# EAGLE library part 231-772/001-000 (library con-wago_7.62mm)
Serie 231, Stiftleiste mit geraden Einlötstiften / Series 231, Male connector with straight solder pins Polzahl / Pole No.: 12 Rastermaß / Pitch: 7.62 mm Bemessungsspannung / Rated Voltage: 630 V Nennstrom / Nominal Current: 16 A Lötstiftlänge: / Solder Pin Length: 5 mm Farbe / Color: orange / orange Stand: 01.01.2012. Die jeweils aktuellen Daten zu diesem Artikel finden Sie in unserem Produktkatalog, den Sie unter www.wago.com einsehen können. As of: 01/01/2012. Please find the newest data for this article in our product catalogue, which can be viewed under www.wago.com.

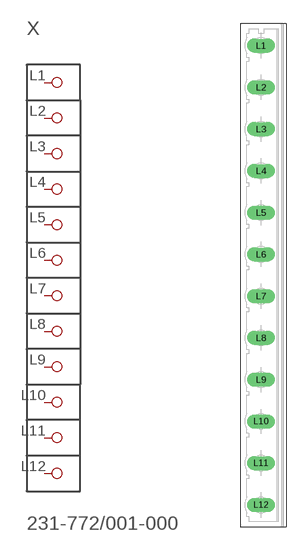
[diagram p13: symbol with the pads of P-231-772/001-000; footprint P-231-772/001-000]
Designator prefix X

## 231-772/001-000  [P-231-772/001-000]
L1  P1
L2  P2
L3  P3
L4  P4
L5  P5
L6  P6
L7  P7
L8  P8
L9  P9
L10  P10
L11  P11
L12  P12

## Footprint P-231-772/001-000 (pad centres in mm)
drill 1.7 long: L1 -0.4,41.91; L2 -0.4,34.29; L3 -0.4,26.67; L4 -0.4,19.05; L5 -0.4,11.43; L6 -0.4,3.81; L7 -0.4,-3.81; L8 -0.4,-11.43; L9 -0.4,-19.05; L10 -0.4,-26.67; L11 -0.4,-34.29; L12 -0.4,-41.91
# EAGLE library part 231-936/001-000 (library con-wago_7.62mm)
Serie 231, Stiftleiste mit abgewinkelten Einlötstiften / Series 231, Male connector with angled solder pins Polzahl / Pole No.: 6 Rastermaß / Pitch: 7.62 mm Bemessungsspannung / Rated Voltage: 630 V Nennstrom / Nominal Current: 12 A Lötstiftlänge: / Solder Pin Length: 3.8 mm Farbe / Color: orange / orange Stand: 01.01.2012. Die jeweils aktuellen Daten zu diesem Artikel finden Sie in unserem Produktkatalog, den Sie unter www.wago.com einsehen können. As of: 01/01/2012. Please find the newest data for this article in our product catalogue, which can be viewed under www.wago.com.

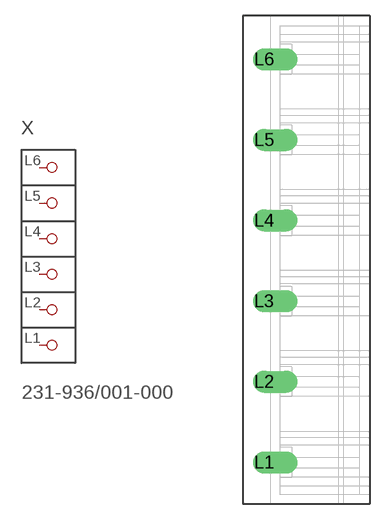
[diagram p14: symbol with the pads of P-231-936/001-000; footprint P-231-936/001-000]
Designator prefix X

## 231-936/001-000  [P-231-936/001-000]
L1  P1
L2  P2
L3  P3
L4  P4
L5  P5
L6  P6

## Footprint P-231-936/001-000 (pad centres in mm)
drill 1.4 offset: L1 -4,-19.15; L2 -4,-11.53; L3 -4,-3.91; L4 -4,3.71; L5 -4,11.33; L6 -4,18.95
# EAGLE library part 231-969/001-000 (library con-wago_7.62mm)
Serie 231, Stiftleiste (für Leiterplatten) Einlötstift abgewinkelt 1,2x1,2 mm / Series 231, Male header (for PCBs) Angled solder pin, 1.2 x 1.2 mm Polzahl / Pole No.: 9 Rastermaß / Pitch: 7.62 mm Bemessungsspannung / Rated Voltage: 630 V Nennstrom / Nominal Current: 16 A Lötstiftlänge: / Solder Pin Length: 3.8 mm Farbe / Color: orange / orange Stand: 01.01.2012. Die jeweils aktuellen Daten zu diesem Artikel finden Sie in unserem Produktkatalog, den Sie unter www.wago.com einsehen können. As of: 01/01/2012. Please find the newest data for this article in our product catalogue, which can be viewed under www.wago.com.

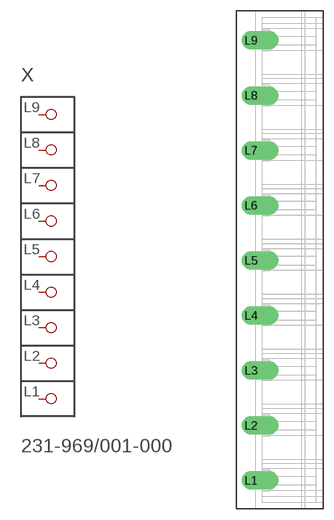
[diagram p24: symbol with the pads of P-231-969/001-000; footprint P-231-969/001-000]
Designator prefix X

## 231-969/001-000  [P-231-969/001-000]
L1  P1
L2  P2
L3  P3
L4  P4
L5  P5
L6  P6
L7  P7
L8  P8
L9  P9

## Footprint P-231-969/001-000 (pad centres in mm)
drill 1.7 offset: L1 -4,-30.58; L2 -4,-22.96; L3 -4,-15.34; L4 -4,-7.72; L5 -4,-0.1; L6 -4,7.52; L7 -4,15.14; L8 -4,22.76; L9 -4,30.38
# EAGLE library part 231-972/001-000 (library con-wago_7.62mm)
Serie 231, Stiftleiste mit abgewinkelten Einlötstiften / Series 231, Male connector with angled solder pins Polzahl / Pole No.: 12 Rastermaß / Pitch: 7.62 mm Bemessungsspannung / Rated Voltage: 630 V Nennstrom / Nominal Current: 16 A Lötstiftlänge: / Solder Pin Length: 3.8 mm Farbe / Color: orange / orange Stand: 01.01.2012. Die jeweils aktuellen Daten zu diesem Artikel finden Sie in unserem Produktkatalog, den Sie unter www.wago.com einsehen können. As of: 01/01/2012. Please find the newest data for this article in our product catalogue, which can be viewed under www.wago.com.

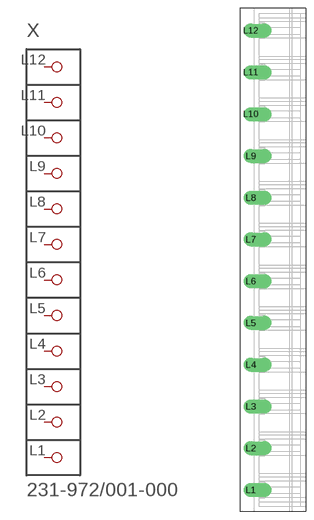
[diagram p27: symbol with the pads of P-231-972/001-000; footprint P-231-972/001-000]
Designator prefix X

## 231-972/001-000  [P-231-972/001-000]
L1  P1
L2  P2
L3  P3
L4  P4
L5  P5
L6  P6
L7  P7
L8  P8
L9  P9
L10  P10
L11  P11
L12  P12

## Footprint P-231-972/001-000 (pad centres in mm)
drill 1.7 offset: L1 -4,-42.01; L2 -4,-34.39; L3 -4,-26.77; L4 -4,-19.15; L5 -4,-11.53; L6 -4,-3.91; L7 -4,3.71; L8 -4,11.33; L9 -4,18.95; L10 -4,26.57; L11 -4,34.19; L12 -4,41.81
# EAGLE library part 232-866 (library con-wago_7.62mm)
Serie 232, Federleiste mit abgewinkelten Einlötstiften / Series 232, Female connector with angled solder pins Polzahl / Pole No.: 6 Rastermaß / Pitch: 7.62 mm Bemessungsspannung / Rated Voltage: 630 V Nennstrom / Nominal Current: 12 A Lötstiftlänge: / Solder Pin Length: 5 mm Farbe / Color: orange / orange Stand: 01.01.2012. Die jeweils aktuellen Daten zu diesem Artikel finden Sie in unserem Produktkatalog, den Sie unter www.wago.com einsehen können. As of: 01/01/2012. Please find the newest data for this article in our product catalogue, which can be viewed under www.wago.com.

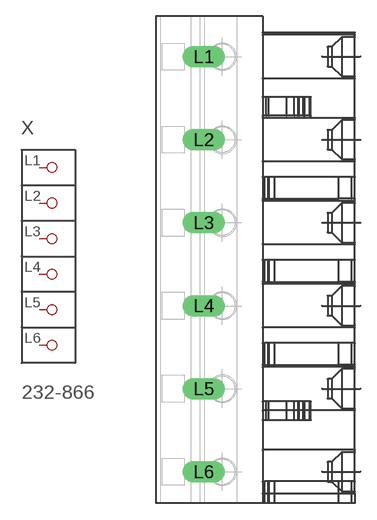
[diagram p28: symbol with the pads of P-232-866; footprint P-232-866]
Designator prefix X

## 232-866  [P-232-866]
L1  P1
L2  P2
L3  P3
L4  P4
L5  P5
L6  P6

## Footprint P-232-866 (pad centres in mm)
drill 1.3 long: L1 -4.976,18.64; L2 -4.976,11.02; L3 -4.976,3.4; L4 -4.976,-4.22; L5 -4.976,-11.84; L6 -4.976,-19.46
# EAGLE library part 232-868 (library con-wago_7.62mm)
Serie 232, Federleiste mit abgewinkelten Einlötstiften / Series 232, Female connector with angled solder pins Polzahl / Pole No.: 8 Rastermaß / Pitch: 7.62 mm Bemessungsspannung / Rated Voltage: 630 V Nennstrom / Nominal Current: 12 A Lötstiftlänge: / Solder Pin Length: 5 mm Farbe / Color: orange / orange Stand: 01.01.2012. Die jeweils aktuellen Daten zu diesem Artikel finden Sie in unserem Produktkatalog, den Sie unter www.wago.com einsehen können. As of: 01/01/2012. Please find the newest data for this article in our product catalogue, which can be viewed under www.wago.com.

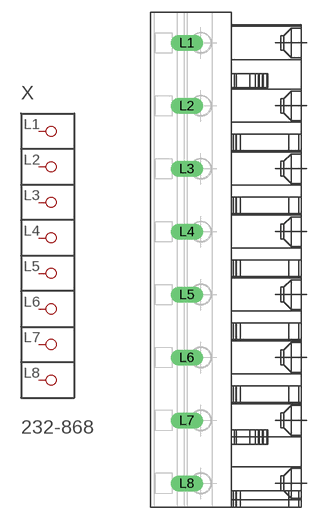
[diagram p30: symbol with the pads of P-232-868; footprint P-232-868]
Designator prefix X

## 232-868  [P-232-868]
L1  P1
L2  P2
L3  P3
L4  P4
L5  P5
L6  P6
L7  P7
L8  P8

## Footprint P-232-868 (pad centres in mm)
drill 1.3 long: L1 -5.046,26.26; L2 -5.046,18.64; L3 -5.046,11.02; L4 -5.046,3.4; L5 -5.046,-4.22; L6 -5.046,-11.84; L7 -5.046,-19.46; L8 -5.046,-27.08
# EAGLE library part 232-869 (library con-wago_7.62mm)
Serie 232, Federleiste mit abgewinkelten Einlötstiften / Series 232, Female connector with angled solder pins Polzahl / Pole No.: 9 Rastermaß / Pitch: 7.62 mm Bemessungsspannung / Rated Voltage: 630 V Nennstrom / Nominal Current: 12 A Lötstiftlänge: / Solder Pin Length: 5 mm Farbe / Color: orange / orange Stand: 01.01.2012. Die jeweils aktuellen Daten zu diesem Artikel finden Sie in unserem Produktkatalog, den Sie unter www.wago.com einsehen können. As of: 01/01/2012. Please find the newest data for this article in our product catalogue, which can be viewed under www.wago.com.

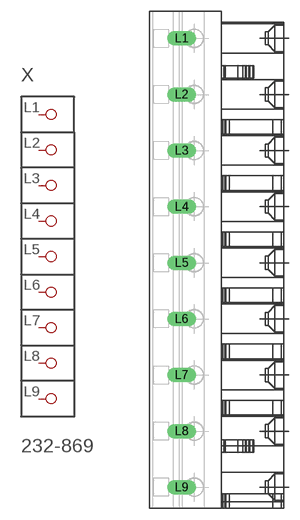
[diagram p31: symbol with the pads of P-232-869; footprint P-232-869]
Designator prefix X

## 232-869  [P-232-869]
L1  P1
L2  P2
L3  P3
L4  P4
L5  P5
L6  P6
L7  P7
L8  P8
L9  P9

## Footprint P-232-869 (pad centres in mm)
drill 1.3 long: L1 -5.083,30.07; L2 -5.083,22.45; L3 -5.083,14.83; L4 -5.083,7.21; L5 -5.083,-0.41; L6 -5.083,-8.03; L7 -5.083,-15.65; L8 -5.083,-23.27; L9 -5.083,-30.89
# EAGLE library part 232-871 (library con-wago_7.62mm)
Serie 232, Federleiste mit abgewinkelten Einlötstiften / Series 232, Female connector with angled solder pins Polzahl / Pole No.: 11 Rastermaß / Pitch: 7.62 mm Bemessungsspannung / Rated Voltage: 630 V Nennstrom / Nominal Current: 12 A Lötstiftlänge: / Solder Pin Length: 5 mm Farbe / Color: orange / orange Stand: 01.01.2012. Die jeweils aktuellen Daten zu diesem Artikel finden Sie in unserem Produktkatalog, den Sie unter www.wago.com einsehen können. As of: 01/01/2012. Please find the newest data for this article in our product catalogue, which can be viewed under www.wago.com.

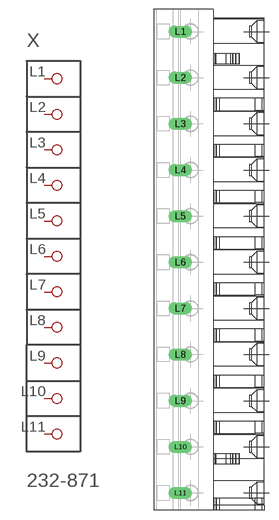
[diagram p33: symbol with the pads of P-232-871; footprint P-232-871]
Designator prefix X

## 232-871  [P-232-871]
L1  P1
L2  P2
L3  P3
L4  P4
L5  P5
L6  P6
L7  P7
L8  P8
L9  P9
L10  P10
L11  P11

## Footprint P-232-871 (pad centres in mm)
drill 1.3 long: L1 -5.156,37.69; L2 -5.156,30.07; L3 -5.156,22.45; L4 -5.156,14.83; L5 -5.156,7.21; L6 -5.156,-0.41; L7 -5.156,-8.03; L8 -5.156,-15.65; L9 -5.156,-23.27; L10 -5.156,-30.89; L11 -5.156,-38.51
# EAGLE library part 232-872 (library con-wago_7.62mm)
Serie 232, Federleiste mit abgewinkelten Einlötstiften / Series 232, Female connector with angled solder pins Polzahl / Pole No.: 12 Rastermaß / Pitch: 7.62 mm Bemessungsspannung / Rated Voltage: 630 V Nennstrom / Nominal Current: 12 A Lötstiftlänge: / Solder Pin Length: 5 mm Farbe / Color: orange / orange Stand: 01.01.2012. Die jeweils aktuellen Daten zu diesem Artikel finden Sie in unserem Produktkatalog, den Sie unter www.wago.com einsehen können. As of: 01/01/2012. Please find the newest data for this article in our product catalogue, which can be viewed under www.wago.com.

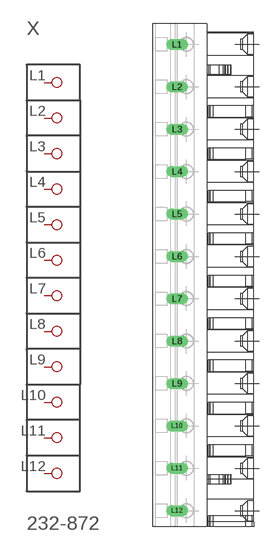
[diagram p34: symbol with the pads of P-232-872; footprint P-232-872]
Designator prefix X

## 232-872  [P-232-872]
L1  P1
L2  P2
L3  P3
L4  P4
L5  P5
L6  P6
L7  P7
L8  P8
L9  P9
L10  P10
L11  P11
L12  P12

## Footprint P-232-872 (pad centres in mm)
drill 1.3 long: L1 -5.193,41.5; L2 -5.193,33.88; L3 -5.193,26.26; L4 -5.193,18.64; L5 -5.193,11.02; L6 -5.193,3.4; L7 -5.193,-4.22; L8 -5.193,-11.84; L9 -5.193,-19.46; L10 -5.193,-27.08; L11 -5.193,-34.7; L12 -5.193,-42.32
